VERSION 5.7 ;
  NOWIREEXTENSIONATPIN ON ;
  DIVIDERCHAR "/" ;
  BUSBITCHARS "[]" ;
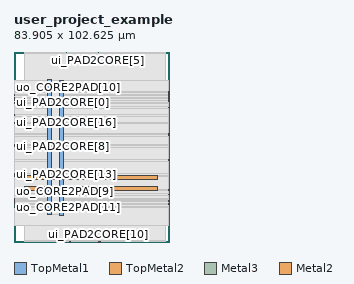
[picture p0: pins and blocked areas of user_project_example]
MACRO user_project_example
  CLASS BLOCK ;
  FOREIGN user_project_example ;
  ORIGIN 0.000 0.000 ;
  SIZE 83.905 BY 102.625 ;
  PIN VGND
    DIRECTION INOUT ;
    USE GROUND ;
    PORT
      LAYER TopMetal1 ;
        RECT 24.460 14.490 26.660 87.160 ;
    END
    PORT
      LAYER TopMetal2 ;
        RECT 5.760 33.820 77.760 36.020 ;
    END
  END VGND
  PIN VPWR
    DIRECTION INOUT ;
    USE POWER ;
    PORT
      LAYER TopMetal1 ;
        RECT 18.260 14.900 20.460 87.570 ;
    END
    PORT
      LAYER TopMetal2 ;
        RECT 5.760 27.620 77.760 29.820 ;
    END
  END VPWR
  PIN clk_i
    DIRECTION INPUT ;
    USE SIGNAL ;
    ANTENNAGATEAREA 1.450800 ;
    PORT
      LAYER Metal3 ;
        RECT 0.000 77.500 0.400 77.900 ;
    END
  END clk_i
  PIN rst_ni
    DIRECTION INPUT ;
    USE SIGNAL ;
    ANTENNAGATEAREA 0.180700 ;
    PORT
      LAYER Metal3 ;
        RECT 0.000 76.660 0.400 77.060 ;
    END
  END rst_ni
  PIN ui_PAD2CORE[0]
    DIRECTION INPUT ;
    USE SIGNAL ;
    ANTENNAGATEAREA 0.180700 ;
    PORT
      LAYER Metal3 ;
        RECT 0.000 74.980 0.400 75.380 ;
    END
  END ui_PAD2CORE[0]
  PIN ui_PAD2CORE[10]
    DIRECTION INPUT ;
    USE SIGNAL ;
    ANTENNAGATEAREA 0.180700 ;
    PORT
      LAYER Metal2 ;
        RECT 45.400 0.000 45.800 0.400 ;
    END
  END ui_PAD2CORE[10]
  PIN ui_PAD2CORE[11]
    DIRECTION INPUT ;
    USE SIGNAL ;
    ANTENNAGATEAREA 0.180700 ;
    PORT
      LAYER Metal2 ;
        RECT 46.360 0.000 46.760 0.400 ;
    END
  END ui_PAD2CORE[11]
  PIN ui_PAD2CORE[12]
    DIRECTION INPUT ;
    USE SIGNAL ;
    ANTENNAGATEAREA 0.180700 ;
    PORT
      LAYER Metal2 ;
        RECT 30.040 0.000 30.440 0.400 ;
    END
  END ui_PAD2CORE[12]
  PIN ui_PAD2CORE[13]
    DIRECTION INPUT ;
    USE SIGNAL ;
    ANTENNAGATEAREA 0.180700 ;
    PORT
      LAYER Metal3 ;
        RECT 0.000 36.340 0.400 36.740 ;
    END
  END ui_PAD2CORE[13]
  PIN ui_PAD2CORE[14]
    DIRECTION INPUT ;
    USE SIGNAL ;
    ANTENNAGATEAREA 0.180700 ;
    PORT
      LAYER Metal3 ;
        RECT 0.000 35.500 0.400 35.900 ;
    END
  END ui_PAD2CORE[14]
  PIN ui_PAD2CORE[15]
    DIRECTION INPUT ;
    USE SIGNAL ;
    ANTENNAGATEAREA 0.180700 ;
    PORT
      LAYER Metal3 ;
        RECT 0.000 52.300 0.400 52.700 ;
    END
  END ui_PAD2CORE[15]
  PIN ui_PAD2CORE[16]
    DIRECTION INPUT ;
    USE SIGNAL ;
    ANTENNAGATEAREA 0.180700 ;
    PORT
      LAYER Metal3 ;
        RECT 0.000 68.260 0.400 68.660 ;
    END
  END ui_PAD2CORE[16]
  PIN ui_PAD2CORE[1]
    DIRECTION INPUT ;
    USE SIGNAL ;
    ANTENNAGATEAREA 0.180700 ;
    PORT
      LAYER Metal3 ;
        RECT 83.505 27.940 83.905 28.340 ;
    END
  END ui_PAD2CORE[1]
  PIN ui_PAD2CORE[2]
    DIRECTION INPUT ;
    USE SIGNAL ;
    ANTENNAGATEAREA 0.180700 ;
    PORT
      LAYER Metal3 ;
        RECT 83.505 43.900 83.905 44.300 ;
    END
  END ui_PAD2CORE[2]
  PIN ui_PAD2CORE[3]
    DIRECTION INPUT ;
    USE SIGNAL ;
    ANTENNAGATEAREA 0.180700 ;
    PORT
      LAYER Metal3 ;
        RECT 83.505 58.180 83.905 58.580 ;
    END
  END ui_PAD2CORE[3]
  PIN ui_PAD2CORE[4]
    DIRECTION INPUT ;
    USE SIGNAL ;
    ANTENNAGATEAREA 0.180700 ;
    PORT
      LAYER Metal3 ;
        RECT 83.505 72.460 83.905 72.860 ;
    END
  END ui_PAD2CORE[4]
  PIN ui_PAD2CORE[5]
    DIRECTION INPUT ;
    USE SIGNAL ;
    ANTENNAGATEAREA 0.180700 ;
    PORT
      LAYER Metal2 ;
        RECT 45.400 102.225 45.800 102.625 ;
    END
  END ui_PAD2CORE[5]
  PIN ui_PAD2CORE[6]
    DIRECTION INPUT ;
    USE SIGNAL ;
    ANTENNAGATEAREA 0.180700 ;
    PORT
      LAYER Metal2 ;
        RECT 28.120 102.225 28.520 102.625 ;
    END
  END ui_PAD2CORE[6]
  PIN ui_PAD2CORE[7]
    DIRECTION INPUT ;
    USE SIGNAL ;
    ANTENNAGATEAREA 0.180700 ;
    PORT
      LAYER Metal3 ;
        RECT 0.000 64.060 0.400 64.460 ;
    END
  END ui_PAD2CORE[7]
  PIN ui_PAD2CORE[8]
    DIRECTION INPUT ;
    USE SIGNAL ;
    ANTENNAGATEAREA 0.180700 ;
    PORT
      LAYER Metal3 ;
        RECT 0.000 51.460 0.400 51.860 ;
    END
  END ui_PAD2CORE[8]
  PIN ui_PAD2CORE[9]
    DIRECTION INPUT ;
    USE SIGNAL ;
    ANTENNAGATEAREA 0.180700 ;
    PORT
      LAYER Metal3 ;
        RECT 83.505 57.340 83.905 57.740 ;
    END
  END ui_PAD2CORE[9]
  PIN uo_CORE2PAD[0]
    DIRECTION OUTPUT ;
    USE SIGNAL ;
    ANTENNADIFFAREA 0.708600 ;
    PORT
      LAYER Metal3 ;
        RECT 83.505 25.420 83.905 25.820 ;
    END
  END uo_CORE2PAD[0]
  PIN uo_CORE2PAD[10]
    DIRECTION OUTPUT ;
    USE SIGNAL ;
    ANTENNADIFFAREA 0.299200 ;
    PORT
      LAYER Metal3 ;
        RECT 0.000 79.180 0.400 79.580 ;
    END
  END uo_CORE2PAD[10]
  PIN uo_CORE2PAD[11]
    DIRECTION OUTPUT ;
    USE SIGNAL ;
    ANTENNADIFFAREA 0.299200 ;
    PORT
      LAYER Metal3 ;
        RECT 0.000 18.700 0.400 19.100 ;
    END
  END uo_CORE2PAD[11]
  PIN uo_CORE2PAD[12]
    DIRECTION OUTPUT ;
    USE SIGNAL ;
    ANTENNADIFFAREA 0.299200 ;
    PORT
      LAYER Metal3 ;
        RECT 0.000 21.220 0.400 21.620 ;
    END
  END uo_CORE2PAD[12]
  PIN uo_CORE2PAD[13]
    DIRECTION OUTPUT ;
    USE SIGNAL ;
    ANTENNADIFFAREA 0.299200 ;
    PORT
      LAYER Metal3 ;
        RECT 83.505 75.820 83.905 76.220 ;
    END
  END uo_CORE2PAD[13]
  PIN uo_CORE2PAD[14]
    DIRECTION OUTPUT ;
    USE SIGNAL ;
    ANTENNADIFFAREA 0.299200 ;
    PORT
      LAYER Metal3 ;
        RECT 0.000 19.540 0.400 19.940 ;
    END
  END uo_CORE2PAD[14]
  PIN uo_CORE2PAD[15]
    DIRECTION OUTPUT ;
    USE SIGNAL ;
    ANTENNADIFFAREA 0.299200 ;
    PORT
      LAYER Metal3 ;
        RECT 83.505 80.020 83.905 80.420 ;
    END
  END uo_CORE2PAD[15]
  PIN uo_CORE2PAD[16]
    DIRECTION OUTPUT ;
    USE SIGNAL ;
    ANTENNADIFFAREA 0.299200 ;
    PORT
      LAYER Metal3 ;
        RECT 0.000 20.380 0.400 20.780 ;
    END
  END uo_CORE2PAD[16]
  PIN uo_CORE2PAD[1]
    DIRECTION OUTPUT ;
    USE SIGNAL ;
    ANTENNADIFFAREA 0.392700 ;
    PORT
      LAYER Metal3 ;
        RECT 83.505 22.060 83.905 22.460 ;
    END
  END uo_CORE2PAD[1]
  PIN uo_CORE2PAD[2]
    DIRECTION OUTPUT ;
    USE SIGNAL ;
    ANTENNADIFFAREA 0.299200 ;
    PORT
      LAYER Metal3 ;
        RECT 83.505 77.500 83.905 77.900 ;
    END
  END uo_CORE2PAD[2]
  PIN uo_CORE2PAD[3]
    DIRECTION OUTPUT ;
    USE SIGNAL ;
    ANTENNADIFFAREA 0.299200 ;
    PORT
      LAYER Metal3 ;
        RECT 83.505 79.180 83.905 79.580 ;
    END
  END uo_CORE2PAD[3]
  PIN uo_CORE2PAD[4]
    DIRECTION OUTPUT ;
    USE SIGNAL ;
    ANTENNADIFFAREA 0.299200 ;
    PORT
      LAYER Metal3 ;
        RECT 83.505 80.860 83.905 81.260 ;
    END
  END uo_CORE2PAD[4]
  PIN uo_CORE2PAD[5]
    DIRECTION OUTPUT ;
    USE SIGNAL ;
    ANTENNADIFFAREA 0.299200 ;
    PORT
      LAYER Metal3 ;
        RECT 83.505 20.380 83.905 20.780 ;
    END
  END uo_CORE2PAD[5]
  PIN uo_CORE2PAD[6]
    DIRECTION OUTPUT ;
    USE SIGNAL ;
    ANTENNADIFFAREA 0.299200 ;
    PORT
      LAYER Metal3 ;
        RECT 83.505 78.340 83.905 78.740 ;
    END
  END uo_CORE2PAD[6]
  PIN uo_CORE2PAD[7]
    DIRECTION OUTPUT ;
    USE SIGNAL ;
    ANTENNADIFFAREA 0.299200 ;
    PORT
      LAYER Metal3 ;
        RECT 0.000 22.060 0.400 22.460 ;
    END
  END uo_CORE2PAD[7]
  PIN uo_CORE2PAD[8]
    DIRECTION OUTPUT ;
    USE SIGNAL ;
    ANTENNADIFFAREA 0.299200 ;
    PORT
      LAYER Metal3 ;
        RECT 83.505 76.660 83.905 77.060 ;
    END
  END uo_CORE2PAD[8]
  PIN uo_CORE2PAD[9]
    DIRECTION OUTPUT ;
    USE SIGNAL ;
    ANTENNADIFFAREA 0.299200 ;
    PORT
      LAYER Metal3 ;
        RECT 0.000 22.900 0.400 23.300 ;
    END
  END uo_CORE2PAD[9]
  OBS
      LAYER GatPoly ;
        RECT 5.760 14.970 77.760 87.090 ;
      LAYER Metal1 ;
        RECT 5.760 14.900 77.760 87.160 ;
      LAYER Metal2 ;
        RECT 5.655 102.015 27.910 102.225 ;
        RECT 28.730 102.015 45.190 102.225 ;
        RECT 46.010 102.015 81.705 102.225 ;
        RECT 5.655 0.610 81.705 102.015 ;
        RECT 5.655 0.100 29.830 0.610 ;
        RECT 30.650 0.100 45.190 0.610 ;
        RECT 46.010 0.100 46.150 0.610 ;
        RECT 46.970 0.100 81.705 0.610 ;
      LAYER Metal3 ;
        RECT 0.400 81.470 83.505 87.040 ;
        RECT 0.400 80.650 83.295 81.470 ;
        RECT 0.400 80.630 83.505 80.650 ;
        RECT 0.400 79.810 83.295 80.630 ;
        RECT 0.400 79.790 83.505 79.810 ;
        RECT 0.610 78.970 83.295 79.790 ;
        RECT 0.400 78.950 83.505 78.970 ;
        RECT 0.400 78.130 83.295 78.950 ;
        RECT 0.400 78.110 83.505 78.130 ;
        RECT 0.610 77.290 83.295 78.110 ;
        RECT 0.400 77.270 83.505 77.290 ;
        RECT 0.610 76.450 83.295 77.270 ;
        RECT 0.400 76.430 83.505 76.450 ;
        RECT 0.400 75.610 83.295 76.430 ;
        RECT 0.400 75.590 83.505 75.610 ;
        RECT 0.610 74.770 83.505 75.590 ;
        RECT 0.400 73.070 83.505 74.770 ;
        RECT 0.400 72.250 83.295 73.070 ;
        RECT 0.400 68.870 83.505 72.250 ;
        RECT 0.610 68.050 83.505 68.870 ;
        RECT 0.400 64.670 83.505 68.050 ;
        RECT 0.610 63.850 83.505 64.670 ;
        RECT 0.400 58.790 83.505 63.850 ;
        RECT 0.400 57.970 83.295 58.790 ;
        RECT 0.400 57.950 83.505 57.970 ;
        RECT 0.400 57.130 83.295 57.950 ;
        RECT 0.400 52.910 83.505 57.130 ;
        RECT 0.610 52.090 83.505 52.910 ;
        RECT 0.400 52.070 83.505 52.090 ;
        RECT 0.610 51.250 83.505 52.070 ;
        RECT 0.400 44.510 83.505 51.250 ;
        RECT 0.400 43.690 83.295 44.510 ;
        RECT 0.400 36.950 83.505 43.690 ;
        RECT 0.610 36.130 83.505 36.950 ;
        RECT 0.400 36.110 83.505 36.130 ;
        RECT 0.610 35.290 83.505 36.110 ;
        RECT 0.400 28.550 83.505 35.290 ;
        RECT 0.400 27.730 83.295 28.550 ;
        RECT 0.400 26.030 83.505 27.730 ;
        RECT 0.400 25.210 83.295 26.030 ;
        RECT 0.400 23.510 83.505 25.210 ;
        RECT 0.610 22.690 83.505 23.510 ;
        RECT 0.400 22.670 83.505 22.690 ;
        RECT 0.610 21.850 83.295 22.670 ;
        RECT 0.400 21.830 83.505 21.850 ;
        RECT 0.610 21.010 83.505 21.830 ;
        RECT 0.400 20.990 83.505 21.010 ;
        RECT 0.610 20.170 83.295 20.990 ;
        RECT 0.400 20.150 83.505 20.170 ;
        RECT 0.610 19.330 83.505 20.150 ;
        RECT 0.400 19.310 83.505 19.330 ;
        RECT 0.610 18.490 83.505 19.310 ;
        RECT 0.400 8.720 83.505 18.490 ;
      LAYER Metal4 ;
        RECT 18.440 14.975 26.480 87.085 ;
      LAYER Metal5 ;
        RECT 18.395 14.810 26.525 87.250 ;
  END
END user_project_example
END LIBRARY

